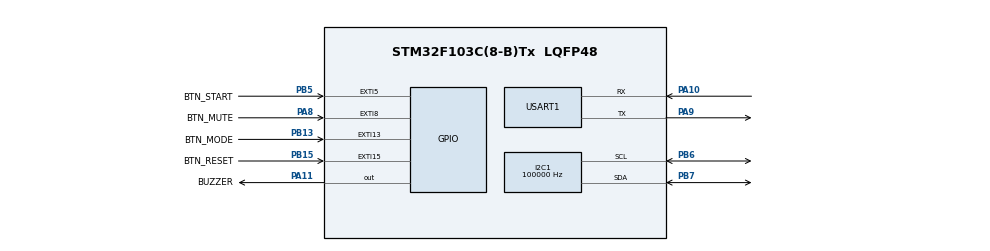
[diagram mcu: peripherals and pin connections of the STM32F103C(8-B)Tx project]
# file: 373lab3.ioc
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I2C1.ClockSpeed=100000
Mcu.Family=STM32F1
Mcu.Name=STM32F103C(8-B)Tx
Mcu.Package=LQFP48
NVIC.EXTI15_10_IRQn=true\:1\:0\:false\:false\:true\:true\:true\:true
NVIC.EXTI9_5_IRQn=true\:1\:0\:false\:false\:true\:true\:true\:true
NVIC.PriorityGroup=NVIC_PRIORITYGROUP_4
NVIC.TIM2_IRQn=true\:0\:0\:false\:false\:true\:true\:true\:true
PA10.Mode=Asynchronous
PA10.Signal=USART1_RX
PA11.GPIO_Label=BUZZER
PA11.Signal=GPIO_Output
PA13.Mode=Serial_Wire
PA13.Signal=SYS_JTMS-SWDIO
PA14.Mode=Serial_Wire
PA14.Signal=SYS_JTCK-SWCLK
PA8.GPIO_Label=BTN_MUTE
PA8.GPIO_ModeDefaultEXTI=GPIO_MODE_IT_FALLING
PA8.GPIO_PuPd=GPIO_PULLUP
PA8.Signal=GPXTI8
PA9.Mode=Asynchronous
PA9.Signal=USART1_TX
PB13.GPIO_Label=BTN_MODE
PB13.GPIO_ModeDefaultEXTI=GPIO_MODE_IT_FALLING
PB13.GPIO_PuPd=GPIO_PULLUP
PB13.Signal=GPXTI13
PB15.GPIO_Label=BTN_RESET
PB15.GPIO_ModeDefaultEXTI=GPIO_MODE_IT_FALLING
PB15.GPIO_PuPd=GPIO_PULLUP
PB15.Signal=GPXTI15
PB5.GPIO_Label=BTN_START
PB5.GPIO_ModeDefaultEXTI=GPIO_MODE_IT_FALLING
PB5.GPIO_PuPd=GPIO_PULLUP
PB5.Signal=GPXTI5
PB6.Mode=I2C
PB6.Signal=I2C1_SCL
PB7.Mode=I2C
PB7.Signal=I2C1_SDA
PD0-OSC_IN.Mode=HSE-External-Oscillator
PD0-OSC_IN.Signal=RCC_OSC_IN
PD1-OSC_OUT.Mode=HSE-External-Oscillator
PD1-OSC_OUT.Signal=RCC_OSC_OUT
ProjectManager.HeapSize=0x200
ProjectManager.StackSize=0x400
ProjectManager.TargetToolchain=STM32CubeIDE
RCC.AHBFreq_Value=72000000
RCC.APB1CLKDivider=RCC_HCLK_DIV2
RCC.APB1Freq_Value=36000000
RCC.APB1TimFreq_Value=72000000
RCC.APB2Freq_Value=72000000
RCC.APB2TimFreq_Value=72000000
RCC.CortexFreq_Value=72000000
RCC.HCLKFreq_Value=72000000
RCC.PLLMUL=RCC_PLL_MUL9
RCC.PLLSourceVirtual=RCC_PLLSOURCE_HSE
RCC.SYSCLKFreq_VALUE=72000000
RCC.SYSCLKSource=RCC_SYSCLKSOURCE_PLLCLK
TIM2.Period=99
TIM2.Prescaler=7199
USART1.VirtualMode=VM_ASYNC
VP_TIM2_VS_ClockSourceINT.Mode=Internal
board=custom

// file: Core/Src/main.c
/* USER CODE BEGIN Header */
/**
  ******************************************************************************
  * @file           : main.c
  * @brief          : Main program body
  ******************************************************************************
  * @attention
  *
  * Copyright (c) 2026 STMicroelectronics.
  * All rights reserved.
  *
  * This software is licensed under terms that can be found in the LICENSE file
  * in the root directory of this software component.
  * If no LICENSE file comes with this software, it is provided AS-IS.
  *
  ******************************************************************************
  */
/* USER CODE END Header */
#include "main.h"

/* USER CODE BEGIN Includes */
#include "studymate_app.h"
/* USER CODE END Includes */

I2C_HandleTypeDef hi2c1;

TIM_HandleTypeDef htim2;

UART_HandleTypeDef huart1;

void SystemClock_Config(void);
static void MX_GPIO_Init(void);
void MX_I2C1_Init(void);
void MX_TIM2_Init(void);
void MX_USART1_UART_Init(void);

int main(void)
{

  /* USER CODE BEGIN 1 */

  /* Always take exception vectors from this application's Flash image.
     This also makes debug launches independent of the BOOT pin mapping. */
  SCB->VTOR = FLASH_BASE;
  __DSB();
  __ISB();

  /* USER CODE END 1 */

  /* MCU Configuration--------------------------------------------------------*/

  /* Reset of all peripherals, Initializes the Flash interface and the Systick. */
  HAL_Init();

  /* Configure the system clock */
  SystemClock_Config();

  /* Initialize all configured peripherals */
  MX_GPIO_Init();
  MX_I2C1_Init();
  MX_TIM2_Init();
  MX_USART1_UART_Init();
  /* USER CODE BEGIN 2 */
  StudyMate_Init(&hi2c1, &huart1);
  if (HAL_TIM_Base_Start_IT(&htim2) != HAL_OK)
  {
    Error_Handler();
  }
  /* USER CODE END 2 */

  /* Infinite loop */
  while (1)
  {

    /* USER CODE BEGIN 3 */
    StudyMate_Task();
    HAL_Delay(1U);
  }

  /* USER CODE END 3 */
}

void SystemClock_Config(void)
{
  RCC_OscInitTypeDef RCC_OscInitStruct = {0};
  RCC_ClkInitTypeDef RCC_ClkInitStruct = {0};

  /** Initializes the RCC Oscillators according to the specified parameters
  * in the RCC_OscInitTypeDef structure.
  */
  RCC_OscInitStruct.OscillatorType = RCC_OSCILLATORTYPE_HSI;
  RCC_OscInitStruct.HSIState = RCC_HSI_ON;
  RCC_OscInitStruct.HSICalibrationValue = RCC_HSICALIBRATION_DEFAULT;
  RCC_OscInitStruct.PLL.PLLState = RCC_PLL_NONE;
  if (HAL_RCC_OscConfig(&RCC_OscInitStruct) != HAL_OK)
  {
    Error_Handler();
  }

  /** Initializes the CPU, AHB and APB buses clocks
  */
  RCC_ClkInitStruct.ClockType = RCC_CLOCKTYPE_HCLK|RCC_CLOCKTYPE_SYSCLK
                              |RCC_CLOCKTYPE_PCLK1|RCC_CLOCKTYPE_PCLK2;
  RCC_ClkInitStruct.SYSCLKSource = RCC_SYSCLKSOURCE_HSI;
  RCC_ClkInitStruct.AHBCLKDivider = RCC_SYSCLK_DIV1;
  RCC_ClkInitStruct.APB1CLKDivider = RCC_HCLK_DIV1;
  RCC_ClkInitStruct.APB2CLKDivider = RCC_HCLK_DIV1;

  if (HAL_RCC_ClockConfig(&RCC_ClkInitStruct, FLASH_LATENCY_0) != HAL_OK)
  {
    Error_Handler();
  }
}

void MX_I2C1_Init(void)
{
  hi2c1.Instance = I2C1;
  hi2c1.Init.ClockSpeed = 100000;
  hi2c1.Init.DutyCycle = I2C_DUTYCYCLE_2;
  hi2c1.Init.OwnAddress1 = 0;
  hi2c1.Init.AddressingMode = I2C_ADDRESSINGMODE_7BIT;
  hi2c1.Init.DualAddressMode = I2C_DUALADDRESS_DISABLE;
  hi2c1.Init.OwnAddress2 = 0;
  hi2c1.Init.GeneralCallMode = I2C_GENERALCALL_DISABLE;
  hi2c1.Init.NoStretchMode = I2C_NOSTRETCH_DISABLE;
  if (HAL_I2C_Init(&hi2c1) != HAL_OK)
  {
    Error_Handler();
  }
}

void MX_TIM2_Init(void)
{
  htim2.Instance = TIM2;
  /* HSI is 8 MHz: 8 MHz / (799 + 1) / (99 + 1) = 100 Hz (10 ms). */
  htim2.Init.Prescaler = 799;
  htim2.Init.CounterMode = TIM_COUNTERMODE_UP;
  htim2.Init.Period = 99;
  htim2.Init.ClockDivision = TIM_CLOCKDIVISION_DIV1;
  htim2.Init.AutoReloadPreload = TIM_AUTORELOAD_PRELOAD_DISABLE;
  if (HAL_TIM_Base_Init(&htim2) != HAL_OK)
  {
    Error_Handler();
  }
}

void MX_USART1_UART_Init(void)
{
  huart1.Instance = USART1;
  huart1.Init.BaudRate = 115200;
  huart1.Init.WordLength = UART_WORDLENGTH_8B;
  huart1.Init.StopBits = UART_STOPBITS_1;
  huart1.Init.Parity = UART_PARITY_NONE;
  huart1.Init.Mode = UART_MODE_TX_RX;
  huart1.Init.HwFlowCtl = UART_HWCONTROL_NONE;
  huart1.Init.OverSampling = UART_OVERSAMPLING_16;
  if (HAL_UART_Init(&huart1) != HAL_OK)
  {
    Error_Handler();
  }
}

static void MX_GPIO_Init(void)
{
  GPIO_InitTypeDef GPIO_InitStruct = {0};

  /* GPIO Ports Clock Enable */
  __HAL_RCC_GPIOA_CLK_ENABLE();
  __HAL_RCC_GPIOB_CLK_ENABLE();

  /*Configure GPIO pin Output Level */
  HAL_GPIO_WritePin(BUZZER_GPIO_Port, BUZZER_Pin, GPIO_PIN_RESET);

  /*Configure GPIO pin : BUZZER_Pin */
  GPIO_InitStruct.Pin = BUZZER_Pin;
  GPIO_InitStruct.Mode = GPIO_MODE_OUTPUT_PP;
  GPIO_InitStruct.Pull = GPIO_NOPULL;
  GPIO_InitStruct.Speed = GPIO_SPEED_FREQ_LOW;
  HAL_GPIO_Init(BUZZER_GPIO_Port, &GPIO_InitStruct);

  /* USER CODE BEGIN MX_GPIO_Init_2 */
  GPIO_InitStruct.Pin = BTN_MUTE_Pin;
  GPIO_InitStruct.Mode = GPIO_MODE_IT_FALLING;
  GPIO_InitStruct.Pull = GPIO_PULLUP;
  HAL_GPIO_Init(BTN_MUTE_GPIO_Port, &GPIO_InitStruct);

  GPIO_InitStruct.Pin = BTN_START_Pin | BTN_MODE_Pin | BTN_RESET_Pin;
  GPIO_InitStruct.Mode = GPIO_MODE_IT_FALLING;
  GPIO_InitStruct.Pull = GPIO_PULLUP;
  HAL_GPIO_Init(GPIOB, &GPIO_InitStruct);

  HAL_NVIC_SetPriority(EXTI9_5_IRQn, 1U, 0U);
  HAL_NVIC_EnableIRQ(EXTI9_5_IRQn);
  HAL_NVIC_SetPriority(EXTI15_10_IRQn, 1U, 0U);
  HAL_NVIC_EnableIRQ(EXTI15_10_IRQn);

  /* USER CODE END MX_GPIO_Init_2 */
}

/* USER CODE BEGIN 4 */
void HAL_GPIO_EXTI_Callback(uint16_t GPIO_Pin)
{
  StudyMate_OnExti(GPIO_Pin);
}

void HAL_TIM_PeriodElapsedCallback(TIM_HandleTypeDef *htim)
{
  if (htim->Instance == TIM2)
  {
    StudyMate_On10msTick();
  }
}

/* USER CODE END 4 */

void Error_Handler(void)
{
  __disable_irq();
  while (1)
  {
  }
}
